VERSION 5.7 ;
  NOWIREEXTENSIONATPIN ON ;
  DIVIDERCHAR "/" ;
  BUSBITCHARS "[]" ;
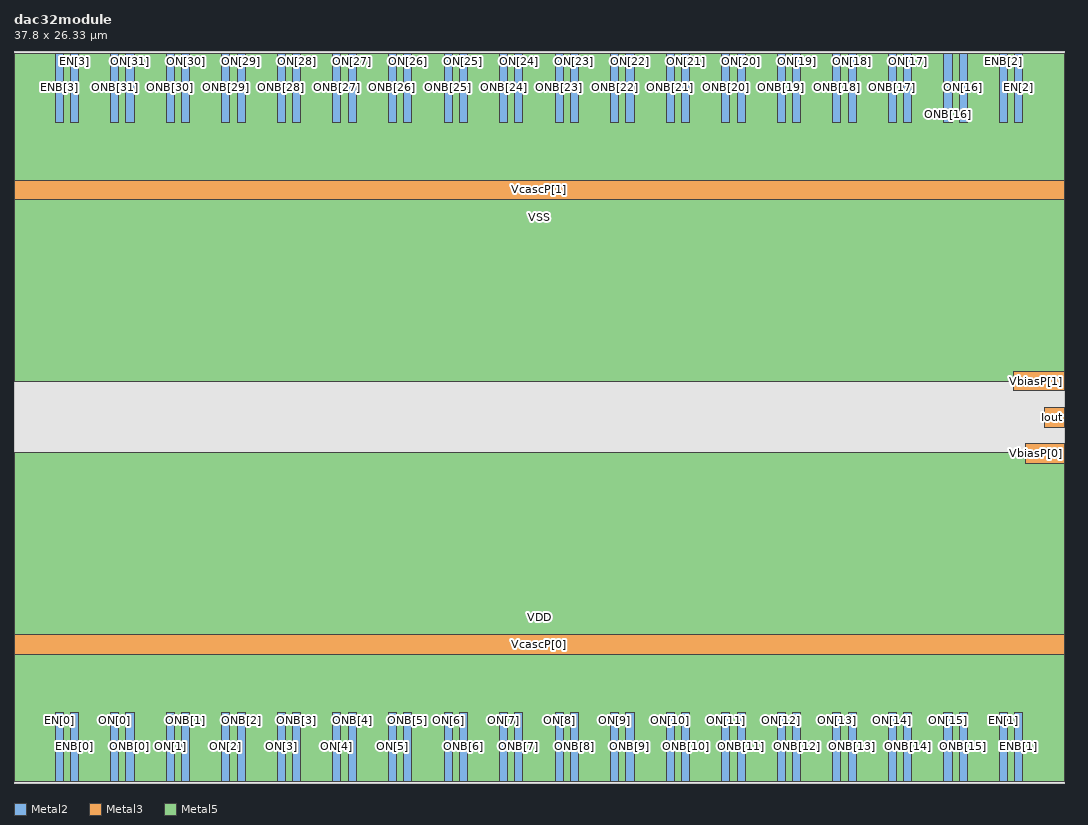
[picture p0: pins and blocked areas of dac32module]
MACRO dac32module
  CLASS BLOCK ;
  FOREIGN dac32module ;
  ORIGIN 0.000 0.070 ;
  SIZE 37.800 BY 26.330 ;
  PIN EN[1]
    ANTENNAGATEAREA 0.039000 ;
    PORT
      LAYER Metal2 ;
        RECT 35.480 0.000 35.770 2.475 ;
    END
  END EN[1]
  PIN ENB[1]
    ANTENNAGATEAREA 0.039000 ;
    PORT
      LAYER Metal2 ;
        RECT 36.030 0.000 36.320 2.475 ;
    END
  END ENB[1]
  PIN EN[2]
    ANTENNAGATEAREA 0.039000 ;
    PORT
      LAYER Metal2 ;
        RECT 36.030 23.715 36.320 26.190 ;
    END
  END EN[2]
  PIN ENB[2]
    ANTENNAGATEAREA 0.039000 ;
    PORT
      LAYER Metal2 ;
        RECT 35.480 23.715 35.770 26.190 ;
    END
  END ENB[2]
  PIN ON[16]
    ANTENNAGATEAREA 0.039000 ;
    PORT
      LAYER Metal2 ;
        RECT 34.030 23.715 34.320 26.190 ;
    END
  END ON[16]
  PIN ONB[16]
    ANTENNAGATEAREA 0.039000 ;
    PORT
      LAYER Metal2 ;
        RECT 33.480 23.715 33.770 26.190 ;
    END
  END ONB[16]
  PIN ON[17]
    ANTENNAGATEAREA 0.039000 ;
    PORT
      LAYER Metal2 ;
        RECT 32.030 23.715 32.320 26.190 ;
    END
  END ON[17]
  PIN ONB[17]
    ANTENNAGATEAREA 0.039000 ;
    PORT
      LAYER Metal2 ;
        RECT 31.480 23.715 31.770 26.190 ;
    END
  END ONB[17]
  PIN ON[18]
    ANTENNAGATEAREA 0.039000 ;
    PORT
      LAYER Metal2 ;
        RECT 30.030 23.715 30.320 26.190 ;
    END
  END ON[18]
  PIN ONB[18]
    ANTENNAGATEAREA 0.039000 ;
    PORT
      LAYER Metal2 ;
        RECT 29.480 23.715 29.770 26.190 ;
    END
  END ONB[18]
  PIN ON[19]
    ANTENNAGATEAREA 0.039000 ;
    PORT
      LAYER Metal2 ;
        RECT 28.030 23.715 28.320 26.190 ;
    END
  END ON[19]
  PIN ONB[19]
    ANTENNAGATEAREA 0.039000 ;
    PORT
      LAYER Metal2 ;
        RECT 27.480 23.715 27.770 26.190 ;
    END
  END ONB[19]
  PIN ON[20]
    ANTENNAGATEAREA 0.039000 ;
    PORT
      LAYER Metal2 ;
        RECT 26.030 23.715 26.320 26.190 ;
    END
  END ON[20]
  PIN ONB[20]
    ANTENNAGATEAREA 0.039000 ;
    PORT
      LAYER Metal2 ;
        RECT 25.480 23.715 25.770 26.190 ;
    END
  END ONB[20]
  PIN ON[21]
    ANTENNAGATEAREA 0.039000 ;
    PORT
      LAYER Metal2 ;
        RECT 24.030 23.715 24.320 26.190 ;
    END
  END ON[21]
  PIN ONB[21]
    ANTENNAGATEAREA 0.039000 ;
    PORT
      LAYER Metal2 ;
        RECT 23.480 23.715 23.770 26.190 ;
    END
  END ONB[21]
  PIN ON[22]
    ANTENNAGATEAREA 0.039000 ;
    PORT
      LAYER Metal2 ;
        RECT 22.030 23.715 22.320 26.190 ;
    END
  END ON[22]
  PIN ONB[22]
    ANTENNAGATEAREA 0.039000 ;
    PORT
      LAYER Metal2 ;
        RECT 21.480 23.715 21.770 26.190 ;
    END
  END ONB[22]
  PIN ON[23]
    ANTENNAGATEAREA 0.039000 ;
    PORT
      LAYER Metal2 ;
        RECT 20.030 23.715 20.320 26.190 ;
    END
  END ON[23]
  PIN ONB[23]
    ANTENNAGATEAREA 0.039000 ;
    PORT
      LAYER Metal2 ;
        RECT 19.480 23.715 19.770 26.190 ;
    END
  END ONB[23]
  PIN ON[24]
    ANTENNAGATEAREA 0.039000 ;
    PORT
      LAYER Metal2 ;
        RECT 18.030 23.715 18.320 26.190 ;
    END
  END ON[24]
  PIN ONB[24]
    ANTENNAGATEAREA 0.039000 ;
    PORT
      LAYER Metal2 ;
        RECT 17.480 23.715 17.770 26.190 ;
    END
  END ONB[24]
  PIN ON[25]
    ANTENNAGATEAREA 0.039000 ;
    PORT
      LAYER Metal2 ;
        RECT 16.030 23.715 16.320 26.190 ;
    END
  END ON[25]
  PIN ONB[25]
    ANTENNAGATEAREA 0.039000 ;
    PORT
      LAYER Metal2 ;
        RECT 15.480 23.715 15.770 26.190 ;
    END
  END ONB[25]
  PIN ON[26]
    ANTENNAGATEAREA 0.039000 ;
    PORT
      LAYER Metal2 ;
        RECT 14.030 23.715 14.320 26.190 ;
    END
  END ON[26]
  PIN ONB[26]
    ANTENNAGATEAREA 0.039000 ;
    PORT
      LAYER Metal2 ;
        RECT 13.480 23.715 13.770 26.190 ;
    END
  END ONB[26]
  PIN ON[27]
    ANTENNAGATEAREA 0.039000 ;
    PORT
      LAYER Metal2 ;
        RECT 12.030 23.715 12.320 26.190 ;
    END
  END ON[27]
  PIN ONB[27]
    ANTENNAGATEAREA 0.039000 ;
    PORT
      LAYER Metal2 ;
        RECT 11.480 23.715 11.770 26.190 ;
    END
  END ONB[27]
  PIN ON[28]
    ANTENNAGATEAREA 0.039000 ;
    PORT
      LAYER Metal2 ;
        RECT 10.030 23.715 10.320 26.190 ;
    END
  END ON[28]
  PIN ONB[28]
    ANTENNAGATEAREA 0.039000 ;
    PORT
      LAYER Metal2 ;
        RECT 9.480 23.715 9.770 26.190 ;
    END
  END ONB[28]
  PIN ON[29]
    ANTENNAGATEAREA 0.039000 ;
    PORT
      LAYER Metal2 ;
        RECT 8.030 23.715 8.320 26.190 ;
    END
  END ON[29]
  PIN ONB[29]
    ANTENNAGATEAREA 0.039000 ;
    PORT
      LAYER Metal2 ;
        RECT 7.480 23.715 7.770 26.190 ;
    END
  END ONB[29]
  PIN ON[30]
    ANTENNAGATEAREA 0.039000 ;
    PORT
      LAYER Metal2 ;
        RECT 6.030 23.715 6.320 26.190 ;
    END
  END ON[30]
  PIN ONB[30]
    ANTENNAGATEAREA 0.039000 ;
    PORT
      LAYER Metal2 ;
        RECT 5.480 23.715 5.770 26.190 ;
    END
  END ONB[30]
  PIN ON[31]
    ANTENNAGATEAREA 0.039000 ;
    PORT
      LAYER Metal2 ;
        RECT 4.030 23.715 4.320 26.190 ;
    END
  END ON[31]
  PIN ONB[31]
    ANTENNAGATEAREA 0.039000 ;
    PORT
      LAYER Metal2 ;
        RECT 3.480 23.715 3.770 26.190 ;
    END
  END ONB[31]
  PIN EN[3]
    ANTENNAGATEAREA 0.039000 ;
    PORT
      LAYER Metal2 ;
        RECT 2.030 23.715 2.320 26.190 ;
    END
  END EN[3]
  PIN ENB[3]
    ANTENNAGATEAREA 0.039000 ;
    PORT
      LAYER Metal2 ;
        RECT 1.480 23.715 1.770 26.190 ;
    END
  END ENB[3]
  PIN ON[0]
    ANTENNAGATEAREA 0.039000 ;
    PORT
      LAYER Metal2 ;
        RECT 3.480 0.000 3.770 2.475 ;
    END
  END ON[0]
  PIN ONB[0]
    ANTENNAGATEAREA 0.039000 ;
    PORT
      LAYER Metal2 ;
        RECT 4.030 0.000 4.320 2.475 ;
    END
  END ONB[0]
  PIN ON[1]
    ANTENNAGATEAREA 0.039000 ;
    PORT
      LAYER Metal2 ;
        RECT 5.480 0.000 5.770 2.475 ;
    END
  END ON[1]
  PIN ONB[1]
    ANTENNAGATEAREA 0.039000 ;
    PORT
      LAYER Metal2 ;
        RECT 6.030 0.000 6.320 2.475 ;
    END
  END ONB[1]
  PIN ON[2]
    ANTENNAGATEAREA 0.039000 ;
    PORT
      LAYER Metal2 ;
        RECT 7.480 0.000 7.770 2.475 ;
    END
  END ON[2]
  PIN ONB[2]
    ANTENNAGATEAREA 0.039000 ;
    PORT
      LAYER Metal2 ;
        RECT 8.030 0.000 8.320 2.475 ;
    END
  END ONB[2]
  PIN ON[3]
    ANTENNAGATEAREA 0.039000 ;
    PORT
      LAYER Metal2 ;
        RECT 9.480 0.000 9.770 2.475 ;
    END
  END ON[3]
  PIN ONB[3]
    ANTENNAGATEAREA 0.039000 ;
    PORT
      LAYER Metal2 ;
        RECT 10.030 0.000 10.320 2.475 ;
    END
  END ONB[3]
  PIN ON[4]
    ANTENNAGATEAREA 0.039000 ;
    PORT
      LAYER Metal2 ;
        RECT 11.480 0.000 11.770 2.475 ;
    END
  END ON[4]
  PIN ONB[4]
    ANTENNAGATEAREA 0.039000 ;
    PORT
      LAYER Metal2 ;
        RECT 12.030 0.000 12.320 2.475 ;
    END
  END ONB[4]
  PIN ON[5]
    ANTENNAGATEAREA 0.039000 ;
    PORT
      LAYER Metal2 ;
        RECT 13.480 0.000 13.770 2.475 ;
    END
  END ON[5]
  PIN ONB[5]
    ANTENNAGATEAREA 0.039000 ;
    PORT
      LAYER Metal2 ;
        RECT 14.030 0.000 14.320 2.475 ;
    END
  END ONB[5]
  PIN ON[6]
    ANTENNAGATEAREA 0.039000 ;
    PORT
      LAYER Metal2 ;
        RECT 15.480 0.000 15.770 2.475 ;
    END
  END ON[6]
  PIN EN[0]
    ANTENNAGATEAREA 0.039000 ;
    PORT
      LAYER Metal2 ;
        RECT 1.480 0.000 1.770 2.475 ;
    END
  END EN[0]
  PIN ENB[0]
    ANTENNAGATEAREA 0.039000 ;
    PORT
      LAYER Metal2 ;
        RECT 2.030 0.000 2.320 2.475 ;
    END
  END ENB[0]
  PIN ONB[6]
    ANTENNAGATEAREA 0.039000 ;
    PORT
      LAYER Metal2 ;
        RECT 16.030 0.000 16.320 2.475 ;
    END
  END ONB[6]
  PIN ON[7]
    ANTENNAGATEAREA 0.039000 ;
    PORT
      LAYER Metal2 ;
        RECT 17.480 0.000 17.770 2.475 ;
    END
  END ON[7]
  PIN ONB[7]
    ANTENNAGATEAREA 0.039000 ;
    PORT
      LAYER Metal2 ;
        RECT 18.030 0.000 18.320 2.475 ;
    END
  END ONB[7]
  PIN ON[8]
    ANTENNAGATEAREA 0.039000 ;
    PORT
      LAYER Metal2 ;
        RECT 19.480 0.000 19.770 2.475 ;
    END
  END ON[8]
  PIN ONB[8]
    ANTENNAGATEAREA 0.039000 ;
    PORT
      LAYER Metal2 ;
        RECT 20.030 0.000 20.320 2.475 ;
    END
  END ONB[8]
  PIN ON[9]
    ANTENNAGATEAREA 0.039000 ;
    PORT
      LAYER Metal2 ;
        RECT 21.480 0.000 21.770 2.475 ;
    END
  END ON[9]
  PIN ONB[9]
    ANTENNAGATEAREA 0.039000 ;
    PORT
      LAYER Metal2 ;
        RECT 22.030 0.000 22.320 2.475 ;
    END
  END ONB[9]
  PIN ON[10]
    ANTENNAGATEAREA 0.039000 ;
    PORT
      LAYER Metal2 ;
        RECT 23.480 0.000 23.770 2.475 ;
    END
  END ON[10]
  PIN ONB[10]
    ANTENNAGATEAREA 0.039000 ;
    PORT
      LAYER Metal2 ;
        RECT 24.030 0.000 24.320 2.475 ;
    END
  END ONB[10]
  PIN ON[11]
    ANTENNAGATEAREA 0.039000 ;
    PORT
      LAYER Metal2 ;
        RECT 25.480 0.000 25.770 2.475 ;
    END
  END ON[11]
  PIN ONB[11]
    ANTENNAGATEAREA 0.039000 ;
    PORT
      LAYER Metal2 ;
        RECT 26.030 0.000 26.320 2.475 ;
    END
  END ONB[11]
  PIN ON[12]
    ANTENNAGATEAREA 0.039000 ;
    PORT
      LAYER Metal2 ;
        RECT 27.480 0.000 27.770 2.475 ;
    END
  END ON[12]
  PIN ONB[12]
    ANTENNAGATEAREA 0.039000 ;
    PORT
      LAYER Metal2 ;
        RECT 28.030 0.000 28.320 2.475 ;
    END
  END ONB[12]
  PIN ON[13]
    ANTENNAGATEAREA 0.039000 ;
    PORT
      LAYER Metal2 ;
        RECT 29.480 0.000 29.770 2.475 ;
    END
  END ON[13]
  PIN ONB[13]
    ANTENNAGATEAREA 0.039000 ;
    PORT
      LAYER Metal2 ;
        RECT 30.030 0.000 30.320 2.475 ;
    END
  END ONB[13]
  PIN ON[14]
    ANTENNAGATEAREA 0.039000 ;
    PORT
      LAYER Metal2 ;
        RECT 31.480 0.000 31.770 2.475 ;
    END
  END ON[14]
  PIN ONB[14]
    ANTENNAGATEAREA 0.039000 ;
    PORT
      LAYER Metal2 ;
        RECT 32.030 0.000 32.320 2.475 ;
    END
  END ONB[14]
  PIN ON[15]
    ANTENNAGATEAREA 0.039000 ;
    PORT
      LAYER Metal2 ;
        RECT 33.480 0.000 33.770 2.475 ;
    END
  END ON[15]
  PIN ONB[15]
    ANTENNAGATEAREA 0.039000 ;
    PORT
      LAYER Metal2 ;
        RECT 34.030 0.000 34.320 2.475 ;
    END
  END ONB[15]
  PIN Iout
    ANTENNADIFFAREA 16.511999 ;
    PORT
      LAYER Metal3 ;
        RECT 37.100 12.745 37.800 13.445 ;
    END
  END Iout
  PIN VbiasP[0]
    ANTENNAGATEAREA 130.500000 ;
    ANTENNADIFFAREA 5.010000 ;
    PORT
      LAYER Metal3 ;
        RECT 36.425 11.445 37.800 12.145 ;
    END
  END VbiasP[0]
  PIN VbiasP[1]
    ANTENNAGATEAREA 130.500000 ;
    ANTENNADIFFAREA 5.010000 ;
    PORT
      LAYER Metal3 ;
        RECT 35.980 14.045 37.800 14.745 ;
    END
  END VbiasP[1]
  PIN VcascP[1]
    ANTENNAGATEAREA 1.755000 ;
    ANTENNADIFFAREA 5.814000 ;
    PORT
      LAYER Metal3 ;
        RECT 0.000 20.930 37.800 21.630 ;
    END
  END VcascP[1]
  PIN VcascP[0]
    ANTENNAGATEAREA 1.755000 ;
    ANTENNADIFFAREA 5.814000 ;
    PORT
      LAYER Metal3 ;
        RECT 0.000 4.560 37.800 5.260 ;
    END
  END VcascP[0]
  PIN VDD
    USE POWER ;
    PORT
      LAYER Metal5 ;
        RECT 0.000 0.000 37.800 11.810 ;
    END
  END VDD
  PIN VSS
    USE GROUND ;
    PORT
      LAYER Metal5 ;
        RECT 0.000 14.380 37.800 26.190 ;
    END
  END VSS
  OBS
      LAYER GatPoly ;
        RECT 0.000 -0.070 37.800 26.260 ;
      LAYER Metal1 ;
        RECT 0.000 0.000 37.800 26.190 ;
      LAYER Metal2 ;
        RECT 0.005 23.505 1.270 26.190 ;
        RECT 2.530 23.505 3.270 26.190 ;
        RECT 4.530 23.505 5.270 26.190 ;
        RECT 6.530 23.505 7.270 26.190 ;
        RECT 8.530 23.505 9.270 26.190 ;
        RECT 10.530 23.505 11.270 26.190 ;
        RECT 12.530 23.505 13.270 26.190 ;
        RECT 14.530 23.505 15.270 26.190 ;
        RECT 16.530 23.505 17.270 26.190 ;
        RECT 18.530 23.505 19.270 26.190 ;
        RECT 20.530 23.505 21.270 26.190 ;
        RECT 22.530 23.505 23.270 26.190 ;
        RECT 24.530 23.505 25.270 26.190 ;
        RECT 26.530 23.505 27.270 26.190 ;
        RECT 28.530 23.505 29.270 26.190 ;
        RECT 30.530 23.505 31.270 26.190 ;
        RECT 32.530 23.505 33.270 26.190 ;
        RECT 34.530 23.505 35.270 26.190 ;
        RECT 36.530 23.505 37.800 26.190 ;
        RECT 0.005 2.685 37.800 23.505 ;
        RECT 0.005 0.000 1.270 2.685 ;
        RECT 2.530 0.000 3.270 2.685 ;
        RECT 4.530 0.000 5.270 2.685 ;
        RECT 6.530 0.000 7.270 2.685 ;
        RECT 8.530 0.000 9.270 2.685 ;
        RECT 10.530 0.000 11.270 2.685 ;
        RECT 12.530 0.000 13.270 2.685 ;
        RECT 14.530 0.000 15.270 2.685 ;
        RECT 16.530 0.000 17.270 2.685 ;
        RECT 18.530 0.000 19.270 2.685 ;
        RECT 20.530 0.000 21.270 2.685 ;
        RECT 22.530 0.000 23.270 2.685 ;
        RECT 24.530 0.000 25.270 2.685 ;
        RECT 26.530 0.000 27.270 2.685 ;
        RECT 28.530 0.000 29.270 2.685 ;
        RECT 30.530 0.000 31.270 2.685 ;
        RECT 32.530 0.000 33.270 2.685 ;
        RECT 34.530 0.000 35.270 2.685 ;
        RECT 36.530 0.000 37.800 2.685 ;
      LAYER Metal3 ;
        RECT 0.000 21.840 37.800 26.190 ;
        RECT 0.000 14.955 37.800 20.720 ;
        RECT 0.000 13.835 35.770 14.955 ;
        RECT 0.000 13.655 37.800 13.835 ;
        RECT 0.000 12.535 36.890 13.655 ;
        RECT 0.000 12.355 37.800 12.535 ;
        RECT 0.000 11.235 36.215 12.355 ;
        RECT 0.000 5.470 37.800 11.235 ;
        RECT 0.000 0.000 37.800 4.350 ;
      LAYER Metal4 ;
        RECT 0.000 0.000 37.800 26.190 ;
  END
END dac32module
END LIBRARY

